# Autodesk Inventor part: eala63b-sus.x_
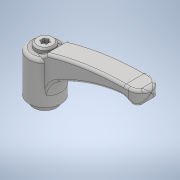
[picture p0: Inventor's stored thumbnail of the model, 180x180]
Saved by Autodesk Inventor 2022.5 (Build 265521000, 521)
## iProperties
Created: 2018-05
Part Number: eala63b-sus.x_
Material: 一般
Document SubType Name: Modeling
Designer: imaocorp
Density: 1 g/cm^3
Appearance: 既定
Sending System: SOLIDWORKS 2016-2016286
MC: AMD64
MC_MODEL: AMD64 Family 21 Model 2 Stepping 0, AuthenticAMD
OS: Windows_NT
FRU: Parasolid Version 28.0, build 224,  7-29-2016
FORMAT: text
GUISE: transmit
KEY: eala63b-sus
FILE: eala63b-sus.x_t
DATE: Fri May 18 11:30:11 2018
Author: imaocorp
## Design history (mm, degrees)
feature "Base1"
node "ソリッド1"
